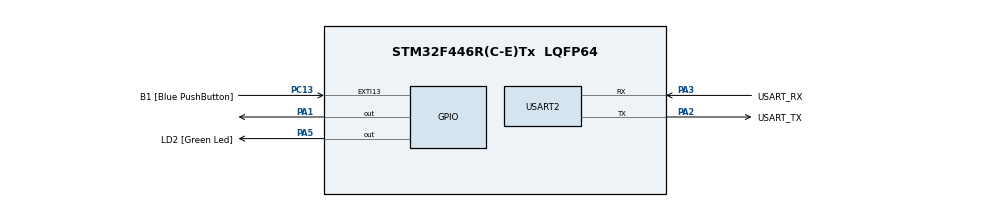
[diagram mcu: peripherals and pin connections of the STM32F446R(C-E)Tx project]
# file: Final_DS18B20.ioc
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Mcu.Family=STM32F4
Mcu.Name=STM32F446R(C-E)Tx
Mcu.Package=LQFP64
NVIC.PriorityGroup=NVIC_PRIORITYGROUP_0
PA1.Signal=GPIO_Output
PA13.GPIO_Label=TMS
PA13.Mode=Serial_Wire
PA13.Signal=SYS_JTMS-SWDIO
PA14.GPIO_Label=TCK
PA14.Mode=Serial_Wire
PA14.Signal=SYS_JTCK-SWCLK
PA2.GPIO_Label=USART_TX
PA2.Mode=Asynchronous
PA2.Signal=USART2_TX
PA3.GPIO_Label=USART_RX
PA3.Mode=Asynchronous
PA3.Signal=USART2_RX
PA5.GPIO_Label=LD2 [Green Led]
PA5.Signal=GPIO_Output
PB3.GPIO_Label=SWO
PB3.Signal=SYS_JTDO-SWO
PC13.GPIO_Label=B1 [Blue PushButton]
PC13.GPIO_ModeDefaultEXTI=GPIO_MODE_IT_FALLING
PC13.Signal=GPXTI13
PC14-OSC32_IN.Mode=LSE-External-Oscillator
PC14-OSC32_IN.Signal=RCC_OSC32_IN
PC15-OSC32_OUT.Mode=LSE-External-Oscillator
PC15-OSC32_OUT.Signal=RCC_OSC32_OUT
PH0-OSC_IN.Mode=HSE-External-Oscillator
PH0-OSC_IN.Signal=RCC_OSC_IN
PH1-OSC_OUT.Mode=HSE-External-Oscillator
PH1-OSC_OUT.Signal=RCC_OSC_OUT
ProjectManager.HeapSize=0x200
ProjectManager.StackSize=0x400
ProjectManager.TargetToolchain=STM32CubeIDE
RCC.48MHZClocksFreq_Value=84000000
RCC.AHBCLKDivider=RCC_SYSCLK_DIV2
RCC.AHBFreq_Value=48000000
RCC.APB1CLKDivider=RCC_HCLK_DIV2
RCC.APB1Freq_Value=24000000
RCC.APB1TimFreq_Value=48000000
RCC.APB2Freq_Value=48000000
RCC.APB2TimFreq_Value=48000000
RCC.CortexFreq_Value=48000000
RCC.FLatency-AdvancedSettings=FLASH_LATENCY_1
RCC.HCLKFreq_Value=48000000
RCC.HSE_VALUE=8000000
RCC.HSI_VALUE=16000000
RCC.PLLM=8
RCC.PLLN=96
RCC.SYSCLKFreq_VALUE=96000000
RCC.SYSCLKSource=RCC_SYSCLKSOURCE_PLLCLK
RCC.USBFreq_Value=96000000
RCC.VCOOutputFreq_Value=192000000
USART2.VirtualMode=VM_ASYNC
board=NUCLEO-F446RE

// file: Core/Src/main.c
/* USER CODE BEGIN Header */
/**
  ******************************************************************************
  * @file           : main.c
  * @brief          : Main program body
  ******************************************************************************
  * @attention
  *
  * Copyright (c) 2024 STMicroelectronics.
  * All rights reserved.
  *
  * This software is licensed under terms that can be found in the LICENSE file
  * in the root directory of this software component.
  * If no LICENSE file comes with this software, it is provided AS-IS.
  *
  ******************************************************************************
  */
/* USER CODE END Header */
#include "main.h"
#include "stdio.h"

UART_HandleTypeDef huart2;

/* Private function prototypes
-----------------------------------------------*/
void SystemClock_Config(void);
static void MX_GPIO_Init(void);
static void MX_USART2_UART_Init(void);
/* USER CODE BEGIN PFP */
void Set_Pin_Output(GPIO_TypeDef*GPIOx, uint16_t GPIO_Pin);
void Set_Pin_Input(GPIO_TypeDef*GPIOx, uint16_t GPIO_Pin);
void delay(uint32_t us);
uint8_t DS18B20_Start(void);
void DS18B20_Write(uint8_t data);
uint8_t DS18B20_Read(void);

#define DS18B20_PORT    				GPIOA
#define DS18B20_PIN						GPIO_PIN_1
#define RESOLUTION_FACTOR_FOR_12_BIT	0.0625
/* USER CODE END PFP */

int main(void)
{

  /* MCU Configuration--------------------------------------------------------*/

  /* Reset of all peripherals, Initializes the Flash interface and the Systick. */
  HAL_Init();

  /* Configure the system clock */
  SystemClock_Config();

  /* Initialize all configured peripherals */
  MX_GPIO_Init();
  MX_USART2_UART_Init();

  /* Infinite loop */
  /* USER CODE BEGIN WHILE */

  uint8_t Presence = 0, Temp_byte1 = 0, Temp_byte2 = 0;
  float temp_data = 0;

  int8_t str[100] = {0};

  while (1)
  {
    /* USER CODE END WHILE */
	  Presence = DS18B20_Start ();
	  HAL_Delay (1);
	  DS18B20_Write (0xCC);  // skip ROM
	  DS18B20_Write (0x44);  // convert t
	  HAL_Delay (800);

	  Presence = DS18B20_Start ();
	  HAL_Delay(1);
	  DS18B20_Write (0xCC);  // skip ROM
	  DS18B20_Write (0xBE);  // Read Scratch-pad

	  Temp_byte1 = DS18B20_Read();
	  Temp_byte2 = DS18B20_Read();

	  temp_data = (float)(((Temp_byte2<<8)|(Temp_byte1))*RESOLUTION_FACTOR_FOR_12_BIT);

	  sprintf(str,"Temperature in degC = %0.2f\r\n", temp_data);
	  HAL_UART_Transmit(&huart2, str, sizeof(str), 1000);
  }
}

void SystemClock_Config(void)
{
  RCC_OscInitTypeDef RCC_OscInitStruct = {0};
  RCC_ClkInitTypeDef RCC_ClkInitStruct = {0};

  /** Configure the main internal regulator output voltage
  */
  __HAL_RCC_PWR_CLK_ENABLE();
  __HAL_PWR_VOLTAGESCALING_CONFIG(PWR_REGULATOR_VOLTAGE_SCALE3);

  /** Initializes the RCC Oscillators according to the specified parameters
  * in the RCC_OscInitTypeDef structure.
  */
  RCC_OscInitStruct.OscillatorType = RCC_OSCILLATORTYPE_HSI;
  RCC_OscInitStruct.HSIState = RCC_HSI_ON;
  RCC_OscInitStruct.HSICalibrationValue = RCC_HSICALIBRATION_DEFAULT;
  RCC_OscInitStruct.PLL.PLLState = RCC_PLL_ON;
  RCC_OscInitStruct.PLL.PLLSource = RCC_PLLSOURCE_HSI;
  RCC_OscInitStruct.PLL.PLLM = 16;
  RCC_OscInitStruct.PLL.PLLN = 336;
  RCC_OscInitStruct.PLL.PLLP = RCC_PLLP_DIV4;
  RCC_OscInitStruct.PLL.PLLQ = 2;
  RCC_OscInitStruct.PLL.PLLR = 2;
  if (HAL_RCC_OscConfig(&RCC_OscInitStruct) != HAL_OK)
  {
    Error_Handler();
  }

  /** Initializes the CPU, AHB and APB buses clocks
  */
  RCC_ClkInitStruct.ClockType = RCC_CLOCKTYPE_HCLK|RCC_CLOCKTYPE_SYSCLK
                              |RCC_CLOCKTYPE_PCLK1|RCC_CLOCKTYPE_PCLK2;
  RCC_ClkInitStruct.SYSCLKSource = RCC_SYSCLKSOURCE_PLLCLK;
  RCC_ClkInitStruct.AHBCLKDivider = RCC_SYSCLK_DIV1;
  RCC_ClkInitStruct.APB1CLKDivider = RCC_HCLK_DIV2;
  RCC_ClkInitStruct.APB2CLKDivider = RCC_HCLK_DIV1;

  if (HAL_RCC_ClockConfig(&RCC_ClkInitStruct, FLASH_LATENCY_2) != HAL_OK)
  {
    Error_Handler();
  }
}

static void MX_USART2_UART_Init(void)
{

  huart2.Instance = USART2;
  huart2.Init.BaudRate = 115200;
  huart2.Init.WordLength = UART_WORDLENGTH_8B;
  huart2.Init.StopBits = UART_STOPBITS_1;
  huart2.Init.Parity = UART_PARITY_NONE;
  huart2.Init.Mode = UART_MODE_TX_RX;
  huart2.Init.HwFlowCtl = UART_HWCONTROL_NONE;
  huart2.Init.OverSampling = UART_OVERSAMPLING_16;
  if (HAL_UART_Init(&huart2) != HAL_OK)
  {
    Error_Handler();
  }

}

static void MX_GPIO_Init(void)
{
  GPIO_InitTypeDef GPIO_InitStruct = {0};

  /* GPIO Ports Clock Enable */
  __HAL_RCC_GPIOC_CLK_ENABLE();
  __HAL_RCC_GPIOH_CLK_ENABLE();
  __HAL_RCC_GPIOA_CLK_ENABLE();
  __HAL_RCC_GPIOB_CLK_ENABLE();

}

void Error_Handler(void)
{
  __disable_irq();
  while (1)
  {
  }
}

void Set_Pin_Output(GPIO_TypeDef*GPIOx, uint16_t GPIO_Pin)
{
	GPIO_InitTypeDef GPIO_InitStruct = {0};

	//Configure GPIO Pin PXx
	GPIO_InitStruct.Pin = GPIO_Pin;
	GPIO_InitStruct.Mode = GPIO_MODE_OUTPUT_OD;
	GPIO_InitStruct.Pull = GPIO_NOPULL;
	GPIO_InitStruct.Speed = GPIO_SPEED_FREQ_LOW;
	HAL_GPIO_Init(GPIOx, &GPIO_InitStruct);
}

void Set_Pin_Input(GPIO_TypeDef*GPIOx, uint16_t GPIO_Pin)
{
	GPIO_InitTypeDef GPIO_InitStruct = {0};

	//Configure GPIO Pin PXx
	GPIO_InitStruct.Pin = GPIO_Pin;
	GPIO_InitStruct.Mode = GPIO_MODE_INPUT;
	GPIO_InitStruct.Pull = GPIO_NOPULL;
	HAL_GPIO_Init(GPIOx, &GPIO_InitStruct);
}

void delay(uint32_t us)
{
	for(int i= 0;i < us;i++)
	{
		for(int j=0;j<5;j++)
		{
			;
		}
	}
}

uint8_t DS18B20_Start(void)
{
	uint8_t Response = 0;
	Set_Pin_Output(DS18B20_PORT, DS18B20_PIN);		//set pin as o/p
	HAL_GPIO_WritePin(DS18B20_PORT, DS18B20_PIN, 0);		//pin pulled to low
	delay(480);		//acc to datasheet

	Set_Pin_Input(DS18B20_PORT, DS18B20_PIN);		//set pin as i/p
	delay(80);

	if(!(HAL_GPIO_ReadPin(DS18B20_PORT, DS18B20_PIN)))
		Response = 1;		//pin is low==presence pulse detected
	else
		Response =-1;

	delay(400);		//480us total

	return Response;
}

void DS18B20_Write(uint8_t data)
{
	Set_Pin_Output(DS18B20_PORT, DS18B20_PIN);		//set pin as o/p
	for(int i=0;i<8;i++)
	{
		if((data&(1<<i))!=0)		//if bit high
		{
			//write 1
			Set_Pin_Output(DS18B20_PORT, DS18B20_PIN);		//set pin as o/p
			HAL_GPIO_WritePin(DS18B20_PORT, DS18B20_PIN, 0);		//pull pin low
			delay(1);

			Set_Pin_Input(DS18B20_PORT, DS18B20_PIN);		//set pin as i/p
			delay(50);		//wait for 60 us
		}
		else		//if bit low
		{
			//write 0
			Set_Pin_Output(DS18B20_PORT, DS18B20_PIN);		//set pin as i/p
			HAL_GPIO_WritePin(DS18B20_PORT, DS18B20_PIN, 0);		//pull pin low
			delay(50);		//wait for 60 us

			Set_Pin_Input(DS18B20_PORT, DS18B20_PIN);		//set pin as i/p
		}
	}
}

uint8_t DS18B20_Read(void)
{
	uint8_t Value = 0;
	Set_Pin_Input(DS18B20_PORT, DS18B20_PIN);		//set pin as i/p
	for(int i=0;i<8;i++)
	{
		Set_Pin_Output(DS18B20_PORT, DS18B20_PIN);		//set pin as o/p
		HAL_GPIO_WritePin(DS18B20_PORT, DS18B20_PIN, 0);		//pull data pin low
		delay(2);		//2us delay

		Set_Pin_Input(DS18B20_PORT, DS18B20_PIN);		//set pin as i/p
		if(HAL_GPIO_ReadPin(DS18B20_PORT, DS18B20_PIN))		//if pin high
		{
			Value |= 1<<i;		//read =1
		}
		delay(60);		//wait 60us
	}
	return Value;
}
